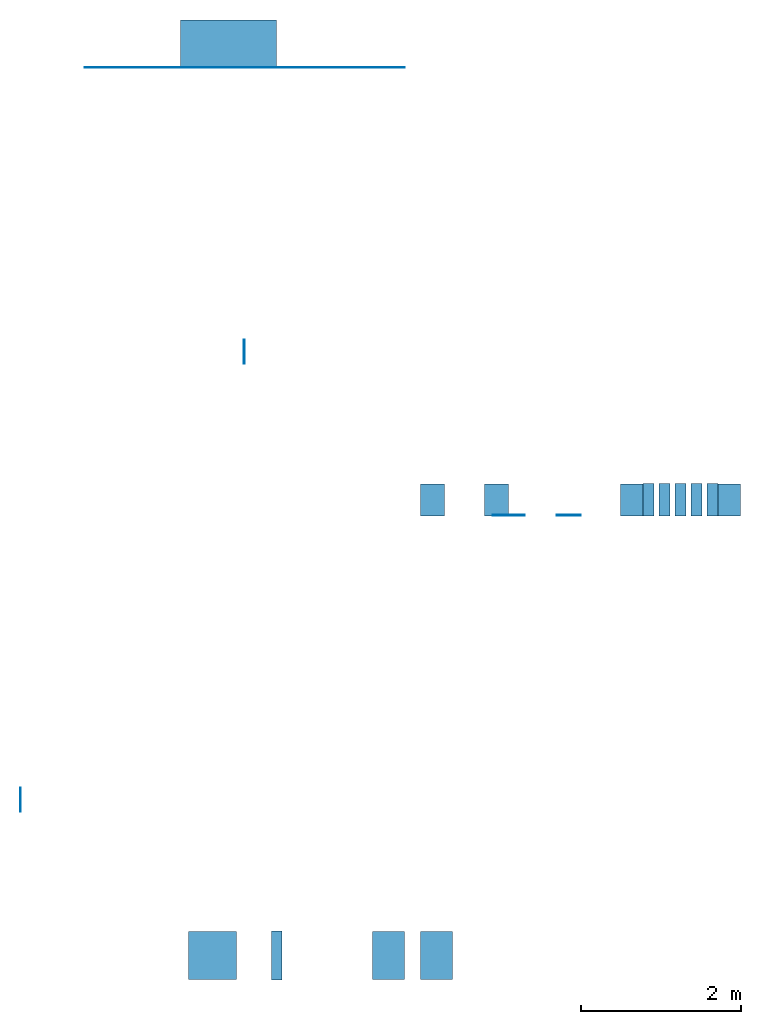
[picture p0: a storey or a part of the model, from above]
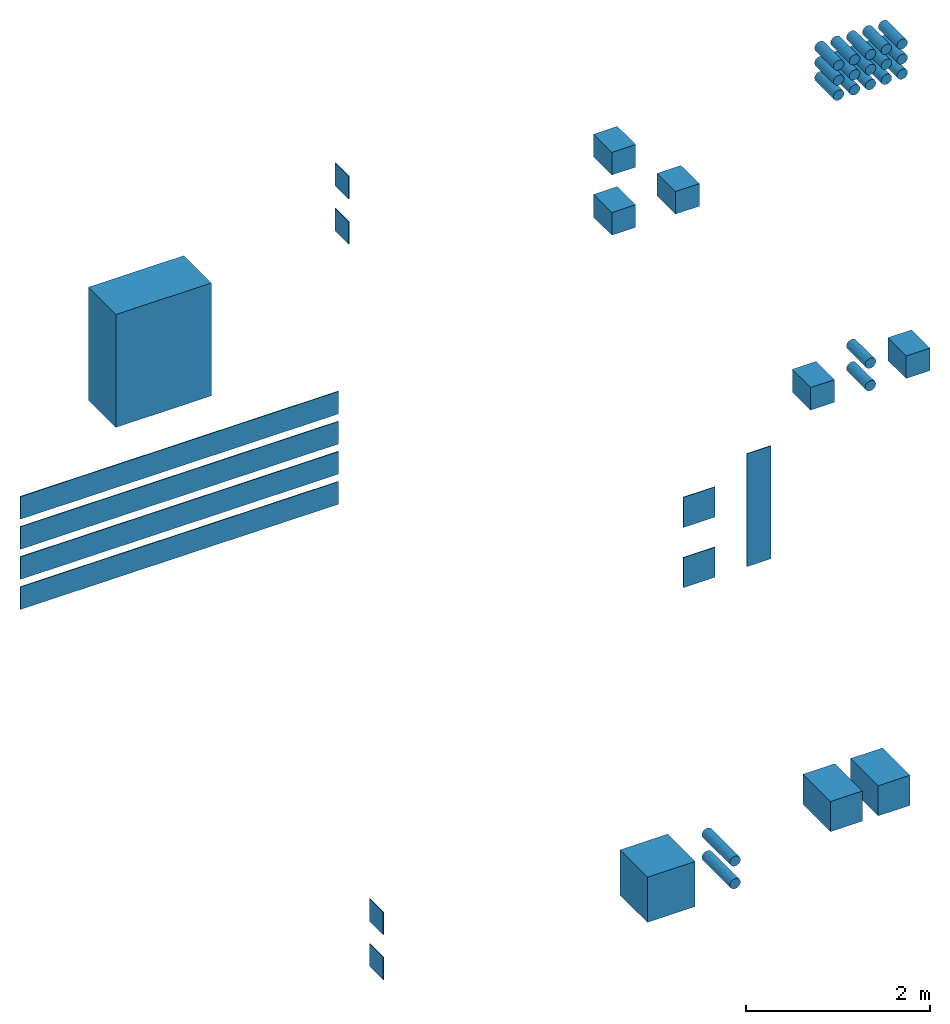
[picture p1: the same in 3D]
Properties of the parts of a building model (IFC2X3)

# File
Description: ViewDefinition[CoordinationView_V2.0, QuantityTakeOffAddOnView], Option [BaseQuantities:On], Option [GridExport:On], Option [Assemblies:On], Option [Bolts:On], Option [Rebars:On], Option [PourObjects:Off], Option [Welds:Off], Option [SurfaceTreatments:On], Option [LocationBy:0], Option [ViewColors:Off], Option [SectionedSpine:Off], Option [PropertySets:On], Option [Export all:Off]
File name: VTZ_geom.ifc
Time: 2024-01-23T11:34:30
Author: VNIPIET\18962017
Organization: Structural Designer
Written by: IFC Database version: Work
Made in: Tekla Structures 2021 Service Pack 11, IFC Export Version: 4.0.0.0 Nov 13 2022

# IfcBuildingStorey, Undefined
In: Undefined
Elevation: 0 mm

# IfcBeam: D133 (19)
In: Undefined
Description: D133; Material: CONCRETE/Opening
BaseQuantities - NetWeight: 0 kg
Name | Length (mm) | OuterSurfaceArea (m2) | NetVolume (m3)
17 x BEAM | 410 | 0.198968 | 0.00568569
2 x BEAM | 610 | 0.282496 | 0.00845919

# IfcElementAssembly (39)
In: Undefined
Name | PredefinedType | Width (mm)
7 x Wall | RIGID_FRAME | 10
4 x Wall | REINFORCEMENT_UNIT | 10
19 x BEAM | REINFORCEMENT_UNIT | 133
5 x Wall | REINFORCEMENT_UNIT | 400
4 x Wall | REINFORCEMENT_UNIT | 600

# IfcWall: 1500*10, Wall
In: Undefined
Description: 1500*10; Material: STEEL/Steel_Undefined
BaseQuantities - Length: 300 mm; OuterSurfaceArea: 0.936 m2; NetVolume: 0.0045 m3; NetWeight: 0 kg; Width: 10 mm; GrossFootprintArea: 0.003 m2

# IfcWall: 1500*600, Wall
In: Undefined
Description: 1500*600; Material: CONCRETE/Opening
BaseQuantities - Length: 1200 mm; OuterSurfaceArea: 6.84 m2; NetVolume: 1.08 m3; NetWeight: 0 kg; Width: 600 mm; GrossFootprintArea: 0.72 m2

# IfcWall: 300*10 (8)
In: Undefined
Description: 300*10
BaseQuantities - NetWeight: 0 kg; Width: 10 mm
Name | Material | Length (mm) | OuterSurfaceArea (m2) | NetVolume (m3) | GrossFootprintArea (m2)
4 x Wall | STEEL/Steel_Undefined | 300 | 0.192 | 0.0009 | 0.003
4 x Wall | CONCRETE/Opening | 4000 | 2.486 | 0.012 | 0.04

# IfcWall: 300*400 (5)
In: Undefined
Description: 300*400; Material: CONCRETE/Opening
BaseQuantities - Length: 300 mm; OuterSurfaceArea: 0.66 m2; NetVolume: 0.036 m3; NetWeight: 0 kg; Width: 400 mm; GrossFootprintArea: 0.12 m2

# IfcWall: 400*10 (2)
In: Undefined
Description: 400*10; Material: STEEL/Steel_Undefined
BaseQuantities - Length: 400 mm; OuterSurfaceArea: 0.336 m2; NetVolume: 0.0016 m3; NetWeight: 0 kg; Width: 10 mm; GrossFootprintArea: 0.004 m2

# IfcWall: 400*600 (2)
In: Undefined
Description: 400*600; Material: CONCRETE/Opening
BaseQuantities - Length: 400 mm; OuterSurfaceArea: 1.28 m2; NetVolume: 0.096 m3; NetWeight: 0 kg; Width: 600 mm; GrossFootprintArea: 0.24 m2

# IfcWall: 600*600, Wall
In: Undefined
Description: 600*600; Material: CONCRETE/Opening
BaseQuantities - Length: 600 mm; OuterSurfaceArea: 2.16 m2; NetVolume: 0.216 m3; NetWeight: 0 kg; Width: 600 mm; GrossFootprintArea: 0.36 m2
